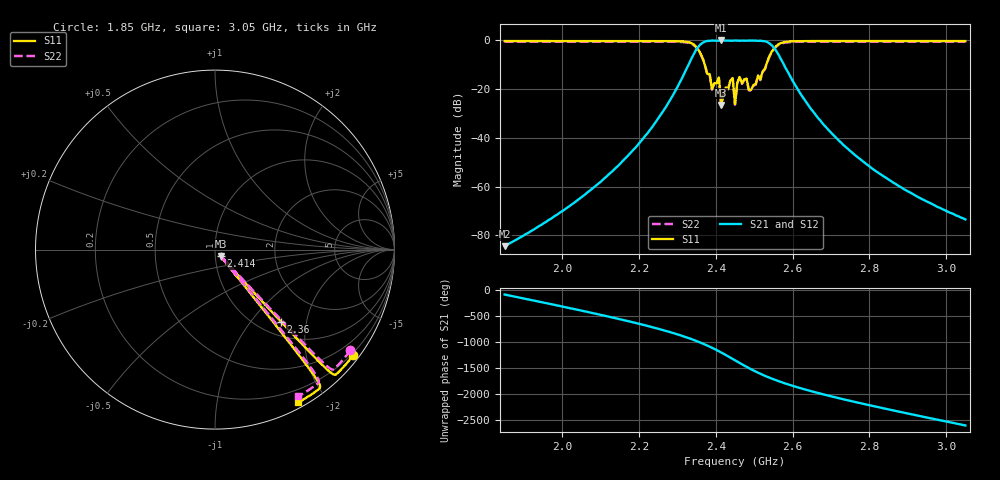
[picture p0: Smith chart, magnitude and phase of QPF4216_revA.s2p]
! written by passband
# GHZ S DB R 50
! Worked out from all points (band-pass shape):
!   201 points, 1.85 GHz to 3.05 GHz, reference 50 ohm
!   highest |S21| = -0.01 dB at 2.414 GHz (marker M1); lowest = -84.4 dB at 1.85 GHz (marker M2)
!   |S21| within 3 dB of the highest: 2.353 GHz to 2.552 GHz (199.2 MHz wide, 8.12 % of centre)
!   lowest |S11| = -26.4 dB at 2.414 GHz (marker M3), VSWR 1.10, Z = 53.1 - j3.8 ohm
!   |S11| at or under -10 dB: 2.371 GHz to 2.531 GHz (159.9 MHz wide, 6.52 % of centre)
!   |S22| runs from -26.7 to -0.5 dB; largest |S21 - S12| = 0
!   S11 on the Smith chart (normalised r, x): 1.85 GHz: 0.15, -2.96; 2.36 GHz: 1.25, -1.43; 2.414 GHz: 1.06, -0.08; 3.05 GHz: 0.06, -1.68
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1.85  -0.27 -37.3  -84.42 -80.7  -84.42 -80.7  -0.53 -36.7
2.054  -0.27 -41.4  -63.83 -37.0  -63.83 -37.0  -0.53 -40.7
2.252  -0.27 -45.4  -31.63 -24.8  -31.63 -24.8  -0.54 -44.7
2.336  -1.09 -47.1  -7.64 141.1  -7.64 141.1  -1.35 -46.3
2.36  -5.29 -47.5  -1.64 72.2  -1.64 72.2  -5.56 -46.8
2.384  -13.74 -48.0  -0.20 -5.9  -0.20 -5.9  -14.01 -47.3
2.39  -19.94 -48.1  -0.05 -27.0  -0.05 -27.0  -20.20 -47.4
2.408  -15.24 -48.5  -0.14 -94.4  -0.14 -94.4  -15.50 -47.7
2.414  -26.44 -48.6  -0.01 -118.1  -0.01 -118.1  -26.71 -47.9
2.432  -19.82 -49.0  -0.05 167.6  -0.05 167.6  -20.09 -48.2
2.444  -15.44 -49.2  -0.13 116.4  -0.13 116.4  -15.71 -48.5
2.45  -26.16 -49.3  -0.01 90.6  -0.01 90.6  -26.42 -48.6
2.456  -17.33 -49.5  -0.09 64.9  -0.09 64.9  -17.60 -48.7
2.468  -17.59 -49.7  -0.08 14.0  -0.08 14.0  -17.86 -48.9
2.492  -20.25 -50.2  -0.04 -82.6  -0.04 -82.6  -20.52 -49.4
2.516  -16.05 -50.7  -0.12 -169.3  -0.12 -169.3  -16.31 -49.9
2.54  -6.27 -51.2  -1.26 114.3  -1.26 114.3  -6.54 -50.4
2.564  -1.51 -51.6  -6.04 46.8  -6.04 46.8  -1.78 -50.8
2.594  -0.41 -52.2  -14.83 -27.9  -14.83 -27.9  -0.68 -51.4
2.654  -0.27 -53.5  -29.28 -156.5  -29.28 -156.5  -0.54 -52.6
2.852  -0.27 -57.4  -57.28 -140.3  -57.28 -140.3  -0.53 -56.6
3.05  -0.27 -61.4  -73.44 -86.4  -73.44 -86.4  -0.53 -60.5
